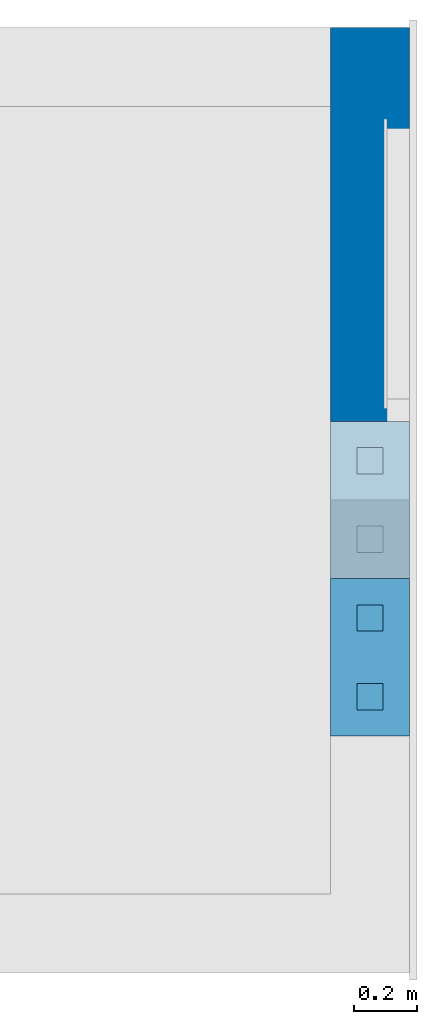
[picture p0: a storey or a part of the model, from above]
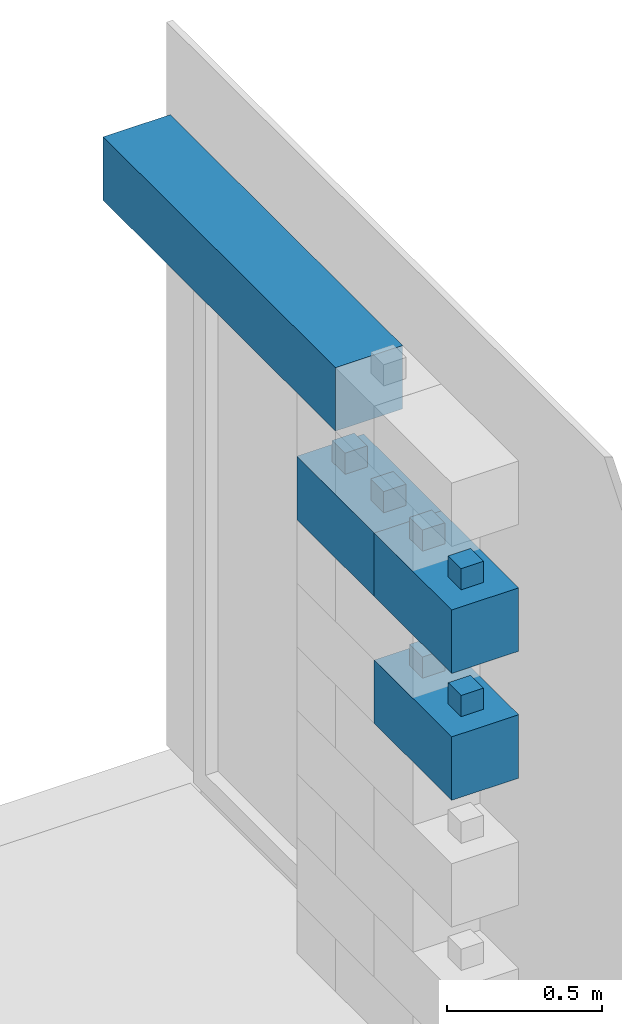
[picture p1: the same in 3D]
Properties of the parts of a building model (IFC4)

# File
Description: ViewDefinition [ReferenceView_V1.2], RevitIdentifiers [ContentGUID: 9b0416a7-ca96-45f1-bb88-8777f9f549b9, VersionGUID: e536b5be-f0a1-41a5-931f-88c381e9b5b1, NumberOfSaves: 17], CoordinateReference [CoordinateBase: Internal Origin, ProjectSite: Internal], ExchangeRequirement [Architecture]
File name: 3dv__Detail__15__215.ifc
Time: 2025-12-19T13:58:14+01:00
Written by: ODA SDAI 25.12
Made in: Autodesk - Revit 26.3.0.37 (ENU) - 26.4.1.0

# IfcSite, Default
RefLatitude: 50, 59, 55, 811462; RefLongitude: 6, 47, 53, 300743; RefElevation: 0 cm

# IfcBuildingStorey (2)
Name | LongName | Elevation (cm)
L00__ABOVE Slab | L00__ABOVE Slab | -4
L01__ABOVE Slab | L01__ABOVE Slab | 256

# IfcBeam: Structural Framing : wll__PARAPET CAP__Metal__sf : Wall Coping w/ H 50mm Nose, Stamped AL Profile
In: L01__ABOVE Slab
Type - PredefinedType: BEAM; Material: _SILL__Sill__Metal
Classification: A 4.4.2 Flashing-uri tabla ambutisata (Uniformat)

# IfcBuildingElementPart (9)
Name | In | Material
_FCD VENT FINISH__Wood Vertical | L00__ABOVE Slab | _FCD VENT FINISH__Wood Vertical
_FND LAYERS__Insulation__Foam Glass__Glapor PG UMB1 | L00__ABOVE Slab | _FND LAYERS__Insulation__Foam Glass__Glapor PG UMB1
_FND LAYERS__Capillary Break Course__Crushed Gravel Layer 16/32 | L00__ABOVE Slab | _FND LAYERS__Capillary Break Course__Crushed Gravel Layer 16/32
_FLR COVERING__Vinyl Tiles | L00__ABOVE Slab | _FLR COVERING__Vinyl Tiles
_FLR LAYERS__Screed__Dry, with Insulation__Fermacell HF | L00__ABOVE Slab | _FLR LAYERS__Screed__Dry, with Insulation__Fermacell HF
_STRUCTURE__Wood CLT | L01__ABOVE Slab | _STRUCTURE__Wood CLT
_GREENERY__Subgrade__Earth | L01__ABOVE Slab | _GREENERY__Subgrade__Earth
_FLR LAYERS__Equalization Infill__Gravel | L01__ABOVE Slab | _FLR LAYERS__Equalization Infill__Gravel
_FLAT ROOF LAYERS__WP Membrane | L01__ABOVE Slab | _FLAT ROOF LAYERS__WP Membrane

# IfcSlab: Floors : Floor : flr__EXT ENCLOSURE__Vegetation, 13.4cm__TriqBriq 2
In: L01__ABOVE Slab
Type - PredefinedType: FLOOR
Classification: A 3.3.6 Green flat roofs (Uniformat)

# IfcSlab: Floors : Floor : flr__INT COVERING__Vinyl Tiles 4.2cm__TriqBriq 2
In: L00__ABOVE Slab
Type - PredefinedType: FLOOR
Classification: A 8.1.5 Floors on a dry screed base (Uniformat)

# IfcSlab: Floors : Floor : flr__STRUCTURE__Wood CLT 10cm__TriqBriq 2
In: L01__ABOVE Slab
Type - PredefinedType: FLOOR
Classification: S 1.2 Floors and roofs (Uniformat)

# IfcSlab: Floors : Floor : flr__WP & INSULATION__Foam Glass 17cm__Under Bsmt Slab, TriqBriq 2
In: L00__ABOVE Slab
Type - PredefinedType: FLOOR
Classification: A 2.1.2 Thermal insulation and waterproofing - horizontal foundation surfaces (Uniformat)

# IfcWall: Columns : wll_s__TIMBER BLOCK__Triqbriq, Full Width__wp : WS25 (17)
Type - PredefinedType: SOLIDWALL; Material: Miscellaneous__Timber Block__Triqbriq, X
Classification: A 1.0.1 Load-bearing modular timber frame construction (Uniformat)
Name (Columns : wll_s__TIMBER BLOCK__Triqbriq, Full Width__wp :...) | In
14 x  WS25 | L00__ABOVE Slab
3 x  WS25 | L01__ABOVE Slab

# IfcWall: Columns : wll_s__TIMBER BLOCK__Triqbriq, Half Width__wp : WS25 (6)
In: L00__ABOVE Slab
Type - PredefinedType: SOLIDWALL; Material: Miscellaneous__Timber Block__Triqbriq, X
Classification: A 1.0.1 Load-bearing modular timber frame construction (Uniformat)

# IfcWall: Structural Framing : wll_s__LINTEL__Triqbriq, Rectangular__wp : Wood
In: L00__ABOVE Slab
Type - PredefinedType: SOLIDWALL; Material: _STRUCTURE__Wood Solid
Classification: A 1.0.3 Modular Wood Frame Wall Add-on Components (Uniformat)

# IfcWall: Walls : Basic Wall : wll__EXT ENCLOSURE__Wood Cladding__TriqBriq 2
In: L00__ABOVE Slab
Type - PredefinedType: STANDARD
Classification: A 4.3.4.2.1 Exterior Partitions (Uniformat)

# IfcWindow: Windows : wdw_s__PANEL__Mobile, Hung, Interior__wp : Glazed, Side hung
In: L00__ABOVE Slab
Type - PredefinedType: WINDOW; Material: _WINDOW__Profile__Aluminium, _WINDOW__Glazing
OverallHeight: 100 cm; OverallWidth: 97 cm

# IfcWindow: Windows : wdw_s__PROFILE__Frame__wp : Wood (3)
In: L00__ABOVE Slab
Type - PredefinedType: WINDOW; Material: _WINDOW__Profile__Aluminium
OverallHeight: 28.3557 cm
Name (Windows : wdw_s__PROFILE__Frame__wp :...) | OverallWidth (cm)
2 x  Wood | 7
 Wood | 10
